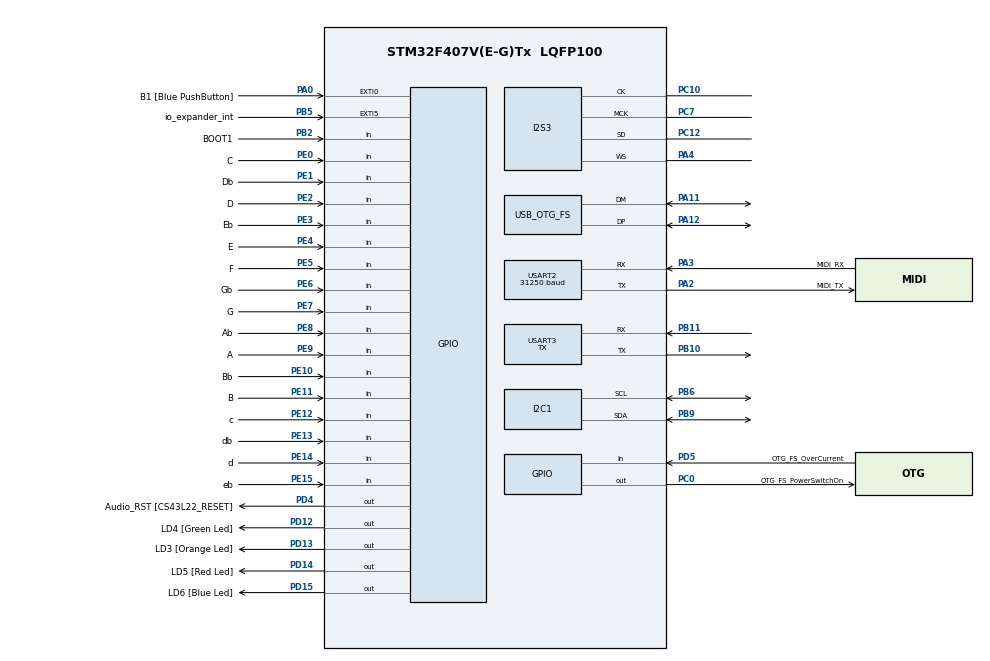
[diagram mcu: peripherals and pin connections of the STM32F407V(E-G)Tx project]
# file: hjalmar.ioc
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Dma.Request0=USART3_TX
Dma.Request1=USART2_RX
Dma.Request2=USART2_TX
Dma.Request3=SPI3_TX
Dma.SPI3_TX.3.Direction=DMA_MEMORY_TO_PERIPH
Dma.SPI3_TX.3.FIFOMode=DMA_FIFOMODE_DISABLE
Dma.SPI3_TX.3.Instance=DMA1_Stream7
Dma.SPI3_TX.3.MemDataAlignment=DMA_MDATAALIGN_HALFWORD
Dma.SPI3_TX.3.MemInc=DMA_MINC_ENABLE
Dma.SPI3_TX.3.Mode=DMA_NORMAL
Dma.SPI3_TX.3.PeriphDataAlignment=DMA_PDATAALIGN_HALFWORD
Dma.SPI3_TX.3.PeriphInc=DMA_PINC_DISABLE
Dma.SPI3_TX.3.Priority=DMA_PRIORITY_LOW
Dma.USART2_RX.1.Direction=DMA_PERIPH_TO_MEMORY
Dma.USART2_RX.1.FIFOMode=DMA_FIFOMODE_DISABLE
Dma.USART2_RX.1.Instance=DMA1_Stream5
Dma.USART2_RX.1.MemDataAlignment=DMA_MDATAALIGN_BYTE
Dma.USART2_RX.1.MemInc=DMA_MINC_ENABLE
Dma.USART2_RX.1.Mode=DMA_NORMAL
Dma.USART2_RX.1.PeriphDataAlignment=DMA_PDATAALIGN_BYTE
Dma.USART2_RX.1.PeriphInc=DMA_PINC_DISABLE
Dma.USART2_RX.1.Priority=DMA_PRIORITY_VERY_HIGH
Dma.USART2_TX.2.Direction=DMA_MEMORY_TO_PERIPH
Dma.USART2_TX.2.FIFOMode=DMA_FIFOMODE_DISABLE
Dma.USART2_TX.2.Instance=DMA1_Stream6
Dma.USART2_TX.2.MemDataAlignment=DMA_MDATAALIGN_BYTE
Dma.USART2_TX.2.MemInc=DMA_MINC_ENABLE
Dma.USART2_TX.2.Mode=DMA_NORMAL
Dma.USART2_TX.2.PeriphDataAlignment=DMA_PDATAALIGN_BYTE
Dma.USART2_TX.2.PeriphInc=DMA_PINC_DISABLE
Dma.USART2_TX.2.Priority=DMA_PRIORITY_LOW
Dma.USART3_TX.0.Direction=DMA_MEMORY_TO_PERIPH
Dma.USART3_TX.0.FIFOMode=DMA_FIFOMODE_DISABLE
Dma.USART3_TX.0.Instance=DMA1_Stream3
Dma.USART3_TX.0.MemDataAlignment=DMA_MDATAALIGN_BYTE
Dma.USART3_TX.0.MemInc=DMA_MINC_ENABLE
Dma.USART3_TX.0.Mode=DMA_NORMAL
Dma.USART3_TX.0.PeriphDataAlignment=DMA_PDATAALIGN_BYTE
Dma.USART3_TX.0.PeriphInc=DMA_PINC_DISABLE
Dma.USART3_TX.0.Priority=DMA_PRIORITY_LOW
I2S3.AudioFreq=I2S_AUDIOFREQ_96K
I2S3.DataFormat=I2S_DATAFORMAT_16B
I2S3.ErrorAudioFreq=-0.3 %
I2S3.FullDuplexMode=I2S_FULLDUPLEXMODE_DISABLE
I2S3.Instance=SPI$Index
I2S3.RealAudioFreq=95.703 KHz
I2S3.VirtualMode=I2S_MODE_MASTER
Mcu.Family=STM32F4
Mcu.Name=STM32F407V(E-G)Tx
Mcu.Package=LQFP100
NVIC.DMA1_Stream3_IRQn=true\:0\:0\:false\:false\:true\:true
NVIC.DMA1_Stream5_IRQn=true\:0\:0\:false\:false\:true\:true
NVIC.DMA1_Stream6_IRQn=true\:0\:0\:false\:false\:true\:true
NVIC.DMA1_Stream7_IRQn=true\:0\:0\:false\:false\:true\:true
NVIC.OTG_FS_IRQn=true\:0\:0\:false\:false\:true\:false
NVIC.PriorityGroup=NVIC_PRIORITYGROUP_0
NVIC.SPI3_IRQn=true\:0\:0\:false\:false\:true\:true
NVIC.TIM6_DAC_IRQn=true\:0\:0\:false\:false\:true\:true
NVIC.TIM7_IRQn=true\:0\:0\:false\:false\:true\:true
NVIC.USART2_IRQn=true\:0\:0\:false\:false\:true\:true
NVIC.USART3_IRQn=true\:0\:0\:false\:false\:true\:true
PA0-WKUP.GPIO_Label=B1 [Blue PushButton]
PA0-WKUP.GPIO_ModeDefaultEXTI=GPIO_MODE_EVT_RISING
PA0-WKUP.GPIO_PuPd=GPIO_NOPULL
PA0-WKUP.Signal=GPXTI0
PA11.Mode=Device_Only
PA11.Signal=USB_OTG_FS_DM
PA12.Mode=Device_Only
PA12.Signal=USB_OTG_FS_DP
PA2.GPIO_Label=MIDI_TX
PA2.Mode=Asynchronous
PA2.Signal=USART2_TX
PA3.GPIO_Label=MIDI_RX
PA3.Mode=Asynchronous
PA3.Signal=USART2_RX
PA4.Mode=Half_Duplex_Master
PA4.Signal=I2S3_WS
PB10.Mode=Asynchronous
PB10.Signal=USART3_TX
PB11.Mode=Asynchronous
PB11.Signal=USART3_RX
PB2.GPIO_Label=BOOT1
PB2.GPIO_Mode=GPIO_MODE_INPUT
PB2.GPIO_PuPd=GPIO_NOPULL
PB2.Signal=GPIO_Input
PB5.GPIO_Label=io_expander_int
PB5.Signal=GPXTI5
PB6.Mode=I2C
PB6.Signal=I2C1_SCL
PB9.Mode=I2C
PB9.Signal=I2C1_SDA
PC0.GPIO_Label=OTG_FS_PowerSwitchOn
PC0.GPIO_PuPd=GPIO_NOPULL
PC0.GPIO_Speed=GPIO_SPEED_FREQ_LOW
PC0.PinState=GPIO_PIN_SET
PC0.Signal=GPIO_Output
PC10.Mode=Half_Duplex_Master
PC10.Signal=I2S3_CK
PC12.Mode=Half_Duplex_Master
PC12.Signal=I2S3_SD
PC7.Mode=Master_Clock_Activated
PC7.Signal=I2S3_MCK
PD12.GPIO_Label=LD4 [Green Led]
PD12.GPIO_PuPd=GPIO_NOPULL
PD12.GPIO_Speed=GPIO_SPEED_FREQ_LOW
PD12.Signal=GPIO_Output
PD13.GPIO_Label=LD3 [Orange Led]
PD13.GPIO_PuPd=GPIO_NOPULL
PD13.GPIO_Speed=GPIO_SPEED_FREQ_LOW
PD13.Signal=GPIO_Output
PD14.GPIO_Label=LD5 [Red Led]
PD14.GPIO_PuPd=GPIO_NOPULL
PD14.GPIO_Speed=GPIO_SPEED_FREQ_LOW
PD14.Signal=GPIO_Output
PD15.GPIO_Label=LD6 [Blue Led]
PD15.GPIO_PuPd=GPIO_NOPULL
PD15.GPIO_Speed=GPIO_SPEED_FREQ_LOW
PD15.Signal=GPIO_Output
PD4.GPIO_Label=Audio_RST [CS43L22_RESET]
PD4.GPIO_PuPd=GPIO_NOPULL
PD4.GPIO_Speed=GPIO_SPEED_FREQ_LOW
PD4.Signal=GPIO_Output
PD5.GPIO_Label=OTG_FS_OverCurrent
PD5.GPIO_Mode=GPIO_MODE_INPUT
PD5.GPIO_PuPd=GPIO_NOPULL
PD5.Signal=GPIO_Input
PE0.GPIO_Label=C
PE0.GPIO_PuPd=GPIO_PULLUP
PE0.Signal=GPIO_Input
PE1.GPIO_Label=Db
PE1.GPIO_PuPd=GPIO_PULLUP
PE1.Signal=GPIO_Input
PE10.GPIO_Label=Bb
PE10.GPIO_PuPd=GPIO_PULLUP
PE10.Signal=GPIO_Input
PE11.GPIO_Label=B
PE11.GPIO_PuPd=GPIO_PULLUP
PE11.Signal=GPIO_Input
PE12.GPIO_Label=c
PE12.GPIO_PuPd=GPIO_PULLUP
PE12.Signal=GPIO_Input
PE13.GPIO_Label=db
PE13.GPIO_PuPd=GPIO_PULLUP
PE13.Signal=GPIO_Input
PE14.GPIO_Label=d
PE14.GPIO_PuPd=GPIO_PULLUP
PE14.Signal=GPIO_Input
PE15.GPIO_Label=eb
PE15.GPIO_PuPd=GPIO_PULLUP
PE15.Signal=GPIO_Input
PE2.GPIO_Label=D
PE2.GPIO_PuPd=GPIO_PULLUP
PE2.Signal=GPIO_Input
PE3.GPIO_Label=Eb
PE3.GPIO_PuPd=GPIO_PULLUP
PE3.Signal=GPIO_Input
PE4.GPIO_Label=E
PE4.GPIO_PuPd=GPIO_PULLUP
PE4.Signal=GPIO_Input
PE5.GPIO_Label=F
PE5.GPIO_PuPd=GPIO_PULLUP
PE5.Signal=GPIO_Input
PE6.GPIO_Label=Gb
PE6.GPIO_PuPd=GPIO_PULLUP
PE6.Signal=GPIO_Input
PE7.GPIO_Label=G
PE7.GPIO_PuPd=GPIO_PULLUP
PE7.Signal=GPIO_Input
PE8.GPIO_Label=Ab
PE8.GPIO_PuPd=GPIO_PULLUP
PE8.Signal=GPIO_Input
PE9.GPIO_Label=A
PE9.GPIO_PuPd=GPIO_PULLUP
PE9.Signal=GPIO_Input
PH0-OSC_IN.Mode=HSE-External-Oscillator
PH0-OSC_IN.Signal=RCC_OSC_IN
PH1-OSC_OUT.Mode=HSE-External-Oscillator
PH1-OSC_OUT.Signal=RCC_OSC_OUT
ProjectManager.HeapSize=0x200
ProjectManager.StackSize=0x400
ProjectManager.TargetToolchain=Makefile
RCC.48MHZClocksFreq_Value=48000000
RCC.AHBFreq_Value=168000000
RCC.APB1CLKDivider=RCC_HCLK_DIV4
RCC.APB1Freq_Value=42000000
RCC.APB1TimFreq_Value=84000000
RCC.APB2CLKDivider=RCC_HCLK_DIV2
RCC.APB2Freq_Value=84000000
RCC.APB2TimFreq_Value=168000000
RCC.CortexFreq_Value=168000000
RCC.HCLKFreq_Value=168000000
RCC.HSE_VALUE=8000000
RCC.HSI_VALUE=16000000
RCC.LSE_VALUE=32768
RCC.PLLI2SN=98
RCC.PLLM=4
RCC.PLLN=168
RCC.PLLQ=7
RCC.SYSCLKFreq_VALUE=168000000
RCC.SYSCLKSource=RCC_SYSCLKSOURCE_PLLCLK
RCC.VCOOutputFreq_Value=336000000
TIM6.Period=1
TIM6.Prescaler=(uint32_t) (SystemCoreClock/8000) - 1
TIM7.Period=1
TIM7.Prescaler=(uint32_t) (SystemCoreClock/800) - 1
USART2.BaudRate=31250
USART2.VirtualMode=VM_ASYNC
USART3.Mode=MODE_TX
USART3.VirtualMode=VM_ASYNC
USB_DEVICE.CLASS_NAME_FS=CDC
USB_DEVICE.VirtualMode-CDC_FS=Cdc
USB_DEVICE.VirtualModeFS=Cdc_FS
USB_OTG_FS.VirtualMode=Device_Only
VP_TIM6_VS_ClockSourceINT.Mode=Enable_Timer
VP_TIM7_VS_ClockSourceINT.Mode=Enable_Timer
VP_USB_DEVICE_VS_USB_DEVICE_CDC_FS.Mode=CDC_FS
board=STM32F4DISCOVERY

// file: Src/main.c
/**
  ******************************************************************************
  * File Name          : main.c
  * Description        : Main program body
  ******************************************************************************
  * This notice applies to any and all portions of this file
  * that are not between comment pairs USER CODE BEGIN and
  * USER CODE END. Other portions of this file, whether
  * inserted by the user or by software development tools
  * are owned by their respective copyright owners.
  *
  * Copyright (c) 2017 STMicroelectronics International N.V.
  * All rights reserved.
  *
  * Redistribution and use in source and binary forms, with or without
  * modification, are permitted, provided that the following conditions are met:
  *
  * 1. Redistribution of source code must retain the above copyright notice,
  *    this list of conditions and the following disclaimer.
  * 2. Redistributions in binary form must reproduce the above copyright notice,
  *    this list of conditions and the following disclaimer in the documentation
  *    and/or other materials provided with the distribution.
  * 3. Neither the name of STMicroelectronics nor the names of other
  *    contributors to this software may be used to endorse or promote products
  *    derived from this software without specific written permission.
  * 4. This software, including modifications and/or derivative works of this
  *    software, must execute solely and exclusively on microcontroller or
  *    microprocessor devices manufactured by or for STMicroelectronics.
  * 5. Redistribution and use of this software other than as permitted under
  *    this license is void and will automatically terminate your rights under
  *    this license.
  *
  * THIS SOFTWARE IS PROVIDED BY STMICROELECTRONICS AND CONTRIBUTORS "AS IS"
  * AND ANY EXPRESS, IMPLIED OR STATUTORY WARRANTIES, INCLUDING, BUT NOT
  * LIMITED TO, THE IMPLIED WARRANTIES OF MERCHANTABILITY, FITNESS FOR A
  * PARTICULAR PURPOSE AND NON-INFRINGEMENT OF THIRD PARTY INTELLECTUAL PROPERTY
  * RIGHTS ARE DISCLAIMED TO THE FULLEST EXTENT PERMITTED BY LAW. IN NO EVENT
  * SHALL STMICROELECTRONICS OR CONTRIBUTORS BE LIABLE FOR ANY DIRECT, INDIRECT,
  * INCIDENTAL, SPECIAL, EXEMPLARY, OR CONSEQUENTIAL DAMAGES (INCLUDING, BUT NOT
  * LIMITED TO, PROCUREMENT OF SUBSTITUTE GOODS OR SERVICES; LOSS OF USE, DATA,
  * OR PROFITS; OR BUSINESS INTERRUPTION) HOWEVER CAUSED AND ON ANY THEORY OF
  * LIABILITY, WHETHER IN CONTRACT, STRICT LIABILITY, OR TORT (INCLUDING
  * NEGLIGENCE OR OTHERWISE) ARISING IN ANY WAY OUT OF THE USE OF THIS SOFTWARE,
  * EVEN IF ADVISED OF THE POSSIBILITY OF SUCH DAMAGE.
  *
  ******************************************************************************
  */

#include "main.h"
#include "stm32f4xx_hal.h"
#include "dma.h"
#include "i2c.h"
#include "i2s.h"
#include "tim.h"
#include "usart.h"
#include "usb_device.h"
#include "gpio.h"

/* USER CODE BEGIN Includes */
#include "envelope.h"
#include "io_expander.h"
#include "midi_cmd.h"
#include "midi_constants.h"
#include "debug_uart.h"
#include "stdlib.h"
#include "audio_interface.h"
#include "audio_gen.h"
#include "work_queue.h"

/* USER CODE END Includes */

/* USER CODE BEGIN PV */
/* Private variables ---------------------------------------------------------*/

static uint64_t ticks_ms = 0;

/* USER CODE END PV */

void SystemClock_Config(void);

/* USER CODE BEGIN PFP */
/* Private function prototypes -----------------------------------------------*/

static void toggle_led(void *data)
{
    (void)data;
    HAL_GPIO_TogglePin(LD4_GPIO_Port, LD4_Pin);
}

/* USER CODE END PFP */

/* USER CODE BEGIN 0 */

void HAL_SYSTICK_Callback(void)
{
    ticks_ms++;

    if ((ticks_ms % 1000) == 0)
    {
        work_queue_add(toggle_led, NULL);
    }
}

/* USER CODE END 0 */

int main(void)
{

    /* MCU Configuration----------------------------------------------------------*/

    /* Reset of all peripherals, Initializes the Flash interface and the Systick. */
    HAL_Init();

    /* Configure the system clock */
    SystemClock_Config();

    /* Initialize all configured peripherals */
    MX_GPIO_Init();
    MX_DMA_Init();
    MX_I2C1_Init();
    MX_I2S3_Init();
    MX_TIM6_Init();
    MX_TIM7_Init();
    MX_USART2_UART_Init();
    MX_USART3_UART_Init();
    MX_USB_DEVICE_Init();

    /* USER CODE BEGIN 2 */
    //init_io_expander();
    init_audio_output();
    init_envelope();
    HAL_GPIO_WritePin(LD4_GPIO_Port, LD4_Pin, GPIO_PIN_SET);
    HAL_GPIO_WritePin(LD3_GPIO_Port, LD3_Pin, GPIO_PIN_RESET);
    HAL_GPIO_WritePin(LD6_GPIO_Port, LD6_Pin, GPIO_PIN_RESET);

    init_debug(64, 127, LOG_LEVEL_INFO);

    if (start_midi_receive() != HAL_OK)
    {
        _Error_Handler(__FILE__, __LINE__);
    }
    audio_gen_wave_form(WAVE_SQUARE);

  /* USER CODE END 2 */

  /* Infinite loop */
    while (1)
    {

  /* USER CODE BEGIN 3 */

        work_queue_process();
/*
        uint32_t pins = read_io_pins();
        wait_ms(10);
        while (!wait_done());
*/
/*      note.cmd_chan = (uint8_t) (NOTE_ON << 4) | MIDI_CHANNEL_0;
      note.note_number = current_note++;

      if(transmit_midi_message((uint8_t *)&note, 4) != HAL_OK){
          _Error_Handler(__FILE__, __LINE__);
      }
      HAL_GPIO_WritePin(GPIOD, LD6_Pin, GPIO_PIN_SET);

      if(wait_ms(100) != HAL_OK)
      {
          _Error_Handler(__FILE__, __LINE__);
      }
      while(!get_midi_tx_state());
      while (!wait_done());
      HAL_GPIO_WritePin(GPIOD, LD6_Pin, GPIO_PIN_RESET);

      note.cmd_chan = (uint8_t) (NOTE_OFF << 4) | MIDI_CHANNEL_0;
      if(transmit_midi_message((uint8_t *)&note, 4) != HAL_OK){
          _Error_Handler(__FILE__, __LINE__);
      }

      if(wait_ms(1000) != HAL_OK)
      {
          _Error_Handler(__FILE__, __LINE__);
      }
      while (!get_midi_tx_state());
      while (!wait_done());*/

  }
  /* USER CODE END 3 */

}

/** System Clock Configuration
*/
void SystemClock_Config(void)
{

  RCC_OscInitTypeDef RCC_OscInitStruct;
  RCC_ClkInitTypeDef RCC_ClkInitStruct;
  RCC_PeriphCLKInitTypeDef PeriphClkInitStruct;

    /**Configure the main internal regulator output voltage
    */
  __HAL_RCC_PWR_CLK_ENABLE();

  __HAL_PWR_VOLTAGESCALING_CONFIG(PWR_REGULATOR_VOLTAGE_SCALE1);

    /**Initializes the CPU, AHB and APB busses clocks
    */
  RCC_OscInitStruct.OscillatorType = RCC_OSCILLATORTYPE_HSE;
  RCC_OscInitStruct.HSEState = RCC_HSE_ON;
  RCC_OscInitStruct.PLL.PLLState = RCC_PLL_ON;
  RCC_OscInitStruct.PLL.PLLSource = RCC_PLLSOURCE_HSE;
  RCC_OscInitStruct.PLL.PLLM = 4;
  RCC_OscInitStruct.PLL.PLLN = 168;
  RCC_OscInitStruct.PLL.PLLP = RCC_PLLP_DIV2;
  RCC_OscInitStruct.PLL.PLLQ = 7;
  if (HAL_RCC_OscConfig(&RCC_OscInitStruct) != HAL_OK)
  {
    _Error_Handler(__FILE__, __LINE__);
  }

    /**Initializes the CPU, AHB and APB busses clocks
    */
  RCC_ClkInitStruct.ClockType = RCC_CLOCKTYPE_HCLK|RCC_CLOCKTYPE_SYSCLK
                              |RCC_CLOCKTYPE_PCLK1|RCC_CLOCKTYPE_PCLK2;
  RCC_ClkInitStruct.SYSCLKSource = RCC_SYSCLKSOURCE_PLLCLK;
  RCC_ClkInitStruct.AHBCLKDivider = RCC_SYSCLK_DIV1;
  RCC_ClkInitStruct.APB1CLKDivider = RCC_HCLK_DIV8;
  RCC_ClkInitStruct.APB2CLKDivider = RCC_HCLK_DIV4;

  if (HAL_RCC_ClockConfig(&RCC_ClkInitStruct, FLASH_LATENCY_5) != HAL_OK)
  {
    _Error_Handler(__FILE__, __LINE__);
  }

  PeriphClkInitStruct.PeriphClockSelection = RCC_PERIPHCLK_I2S;
  PeriphClkInitStruct.PLLI2S.PLLI2SN = 192;
  PeriphClkInitStruct.PLLI2S.PLLI2SR = 2;
  if (HAL_RCCEx_PeriphCLKConfig(&PeriphClkInitStruct) != HAL_OK)
  {
    _Error_Handler(__FILE__, __LINE__);
  }

    /**Configure the Systick interrupt time
    */
  HAL_SYSTICK_Config(HAL_RCC_GetHCLKFreq()/1000);

    /**Configure the Systick
    */
  HAL_SYSTICK_CLKSourceConfig(SYSTICK_CLKSOURCE_HCLK);

  /* SysTick_IRQn interrupt configuration */
  HAL_NVIC_SetPriority(SysTick_IRQn, 0, 0);
}

void _Error_Handler(char * file, int line)
{
  /* USER CODE BEGIN Error_Handler_Debug */
  /* User can add his own implementation to report the HAL error return state */
  while(1)
  {
      HAL_UART_AbortTransmit(&huart3);
      char tx_msg[64] = {0};
      sprintf(tx_msg,"error in %s Line %d\r\n", file, line);
      while(huart2.gState != HAL_UART_STATE_READY);
      HAL_UART_Transmit_DMA(&huart3, (uint8_t *)tx_msg, 64);
      while(huart2.gState != HAL_UART_STATE_READY);
      HAL_UART_DeInit(&huart3);
      HAL_UART_DeInit(&huart2);
      HAL_UART_AbortTransmit(&huart3);

      //if (huart1 == HAL_ERROR){
          HAL_GPIO_WritePin(GPIOD, LD5_Pin, GPIO_PIN_SET);
      //}

  }
  /* USER CODE END Error_Handler_Debug */
}

/************************ (C) COPYRIGHT STMicroelectronics *****END OF FILE****/
